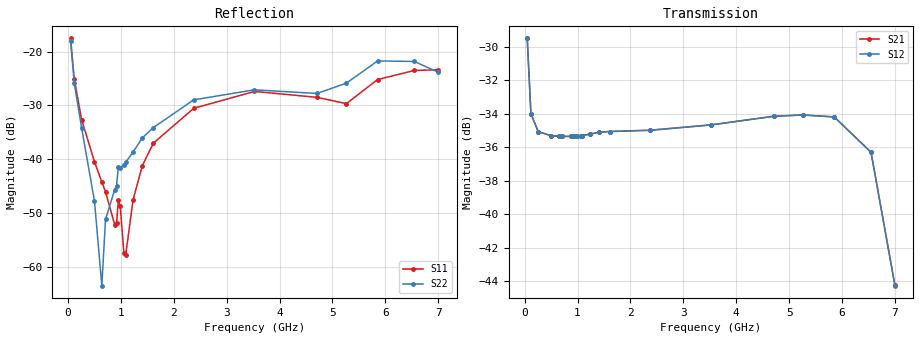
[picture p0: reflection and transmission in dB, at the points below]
! Integrated Device Technology
! Corporate Headquarters
! 6024 Silver Creek Valley Road
! San Jose, CA 95138  USA
! Phone:  1-408-284-8200
! Toll Free:  1-800-223-1366
! Webpage:  http://www.idt.com/
! Timing and RF Division
! 515 Groton Road, Suite 102
! Westford, MA 01886-6024
! Device:  F2258
! Description: Voltage Variable RF Attenuator
! Frequency:  50.0 -  6000.00 MHz
! Package:  3x3 mm Thin QFN Plastic Package: 16 pin
! Ports:  2 RF, 2 DC
!  Pin  1  = NC
!  Pin  2  = NC
!  Pin  3  = RF2  = Port 2
!  Pin  4  = GND
!  Pin  5  = Vdd
!  Pin  6  = NC
!  Pin  7  = VCTRL
!  Pin  8  = NC
!  Pin  9  = GND
!  Pin 10  = RF1  = Port 1
!  Pin 11  = NC
!  Pin 12  = NC
!  Pin 13  = NC
!  Pin 14  = NC
!  Pin 15  = NC
!  Pin 16  = NC
! Vcntrl:  2.180 Volts
! Vdd:  +3.300 Volts
! Current:  1.151 mA
! Data:  The device was measured on a the F2258 evaluation board which has
!  individual transmission lines to the RF pins.  Data was collected
!  using a calibrated network analyzer.  The evaluation board was
!  de-embedded using a TRL calibration technique.
!  The reference plane is the edge of the package pin.
! Misc:  SN 10
!  Action Tracker AT0285
! Date Measured:  2014-12-10
! Date:  2016-01-13  MJV
! Note:
!  Integrated Device Technology supplies this data as a sample of measured
!  data at the package pin for this product.  Your particular data for this
!  product may vary.
!  Data was taken at 25 degrees C.
!  Integrated Device Technology reserves the right to change this data at anytime.
!Freq_(GHz)  S11M_(dB)  S11P_(deg)  S21M_(dB)  S21P_(deg)  S12M_(dB)  S12P_(deg)  S22M_(dB)  S22P_(deg)
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# GHz S dB R 50
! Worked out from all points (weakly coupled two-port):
!   201 points, 50 MHz to 7 GHz, reference 50 ohm
!   highest |S21| = -29.49 dB at 50 MHz (marker M1); lowest = -44.3 dB at 7 GHz (marker M2)
!   lowest |S11| = -57.7 dB at 1.093 GHz (marker M3), VSWR 1.00, Z = 49.9 + j0.113 ohm
!   |S11| at or under -10 dB: start of sweep to end of sweep
!   |S22| runs from -63.4 to -18.0 dB; largest |S21 - S12| = 7.8e-05
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0.05  -17.55 -111.0  -29.49 -68.1  -29.49 -68.1  -17.97 -110.7
0.1195  -25.12 -106.9  -34.00 -36.7  -34.00 -36.7  -25.87 -104.6
0.2585  -32.62 -111.9  -35.07 -18.7  -35.07 -18.7  -34.16 -106.1
0.50175  -40.46 -122.0  -35.31 -11.2  -35.31 -11.2  -47.75 -113.1
0.64075  -44.20 -128.0  -35.34 -9.7  -35.34 -9.7  -63.45 149.8
0.71025  -46.03 -137.8  -35.35 -9.2  -35.35 -9.2  -51.15 100.2
0.884  -52.15 166.3  -35.35 -8.5  -35.35 -8.5  -45.62 94.1
0.91875  -51.89 150.9  -35.34 -8.4  -35.34 -8.4  -44.95 93.7
0.9535  -47.52 -162.9  -35.35 -8.3  -35.35 -8.3  -41.37 109.1
0.98825  -48.69 -174.2  -35.33 -8.2  -35.34 -8.2  -41.63 106.0
1.05775  -57.38 155.1  -35.31 -8.0  -35.31 -8.0  -40.97 90.0
1.0925  -57.70 119.5  -35.30 -8.0  -35.30 -7.9  -40.54 86.5
1.2315  -47.51 47.3  -35.22 -8.0  -35.22 -8.0  -38.64 66.5
1.40525  -41.21 33.7  -35.10 -8.7  -35.10 -8.6  -36.03 56.3
1.61375  -37.01 32.9  -35.06 -9.7  -35.06 -9.7  -34.11 45.8
2.37825  -30.53 48.2  -34.98 -13.4  -34.99 -13.3  -28.96 39.3
3.525  -27.40 91.6  -34.66 -19.8  -34.67 -19.8  -27.10 64.6
4.7065  -28.49 95.6  -34.15 -29.0  -34.15 -29.0  -27.78 56.1
5.2625  -29.67 54.3  -34.07 -35.2  -34.07 -35.1  -25.86 18.7
5.85325  -25.19 29.8  -34.19 -45.7  -34.19 -45.7  -21.74 -4.2
6.54825  -23.51 45.1  -36.30 -66.4  -36.31 -66.5  -21.84 -39.0
7  -23.38 84.4  -44.26 -61.9  -44.28 -61.3  -23.84 -129.5
